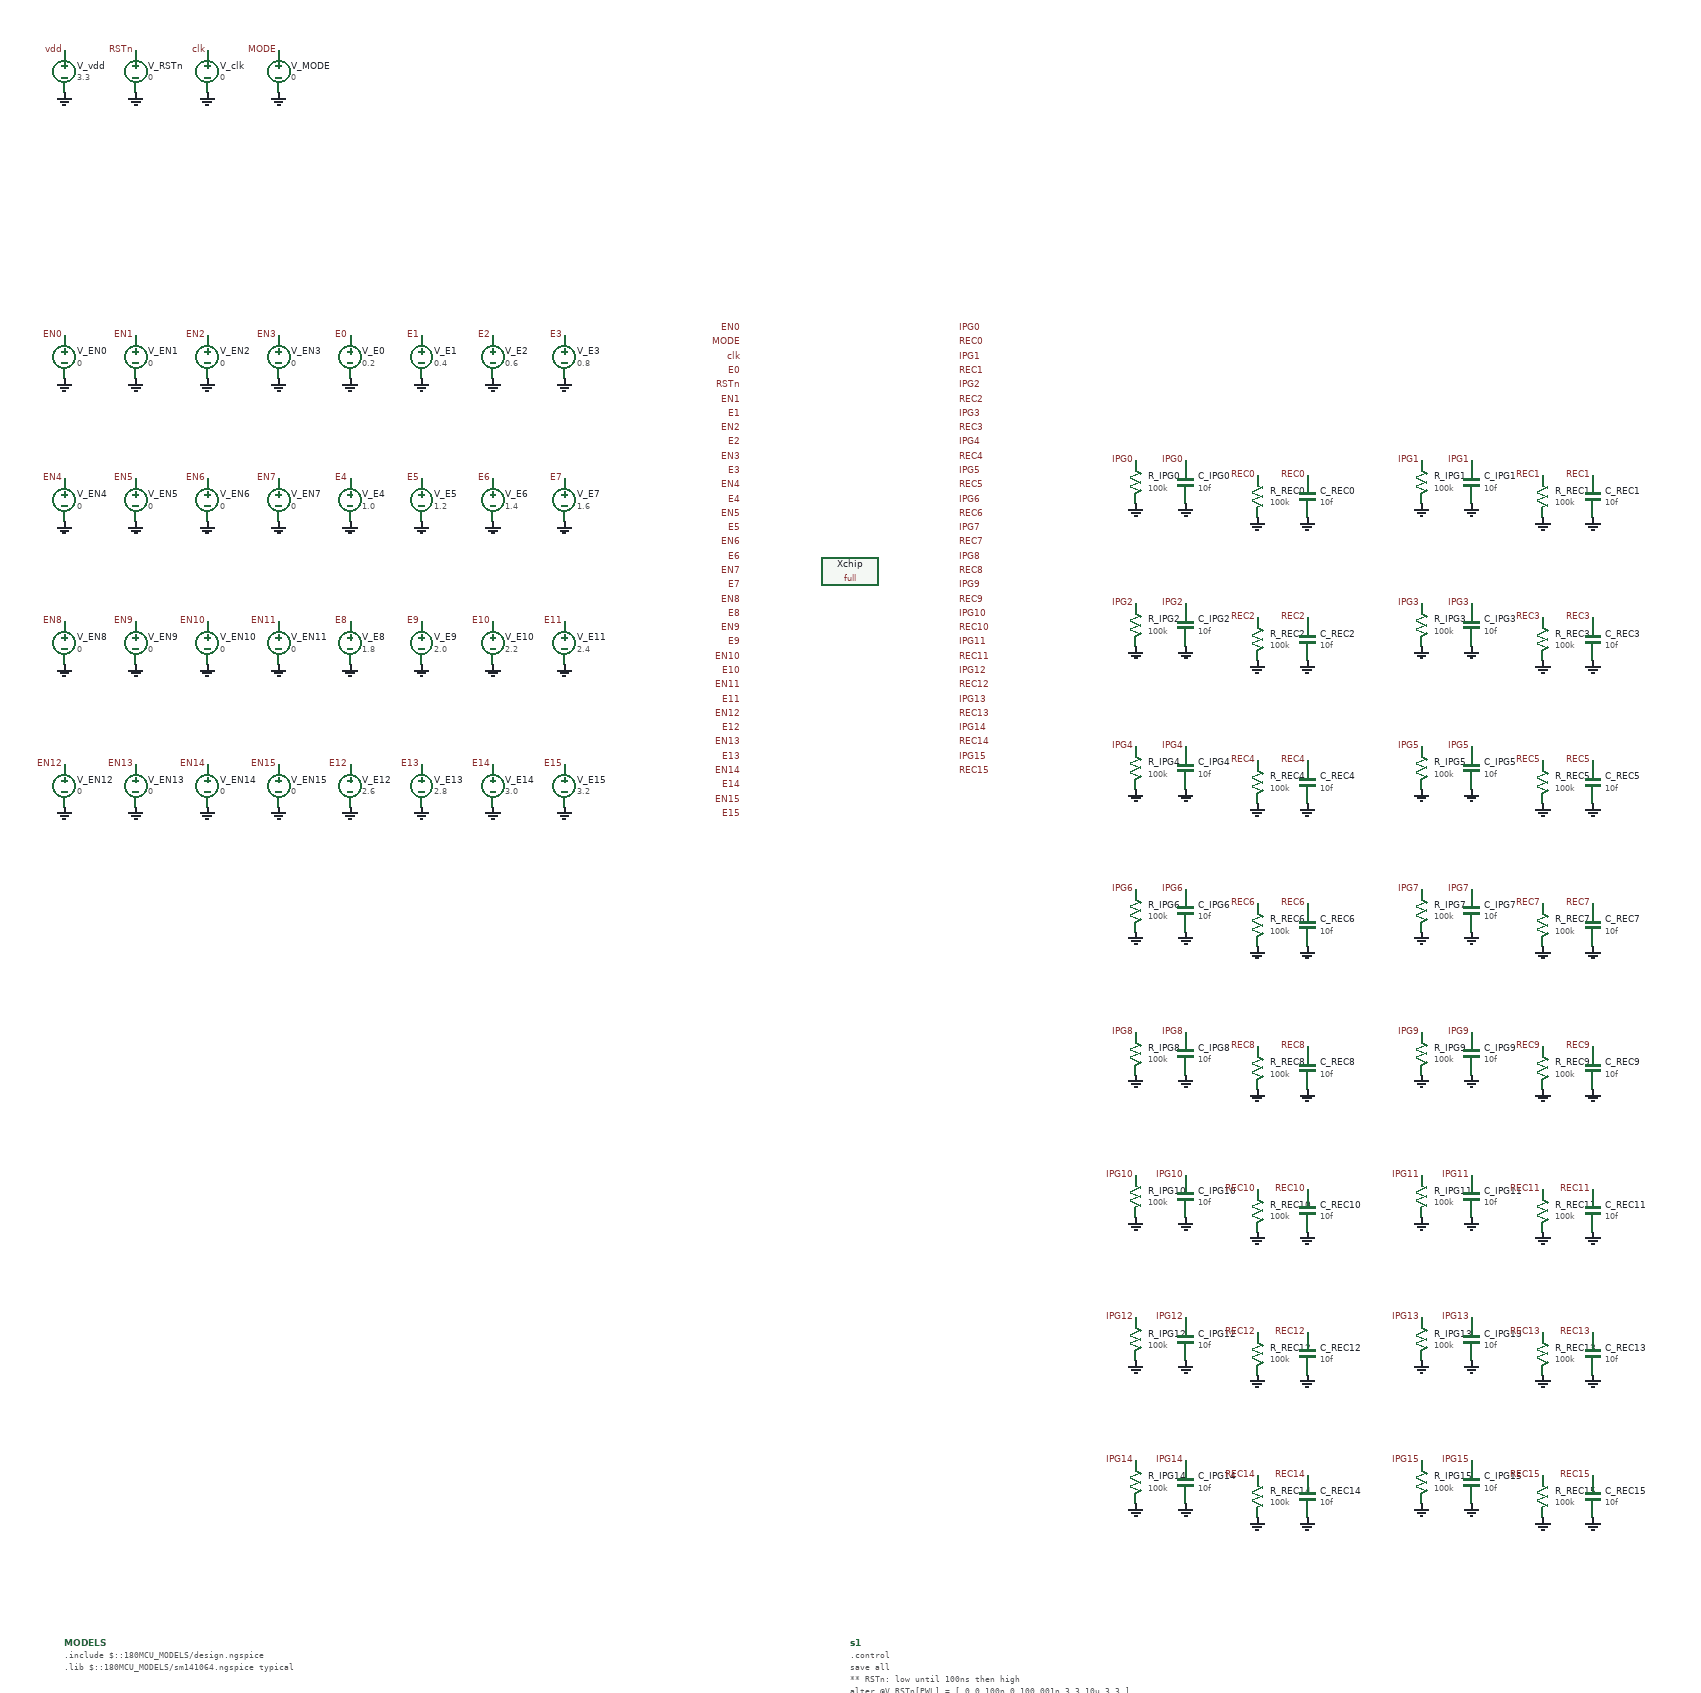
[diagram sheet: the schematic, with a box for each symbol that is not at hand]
v {xschem version=3.4.7 file_version=1.2}
G {}
K {}
V {}
S {}
E {}
C {full.sym} 0 0 0 0 {name=Xchip}
C {lab_wire.sym} -150 -340 0 0 {name=p_EN0_at_chip sig_type=std_logic lab=EN0}
C {lab_wire.sym} -150 -320 0 0 {name=p_MODE_at_chip sig_type=std_logic lab=MODE}
C {lab_wire.sym} -150 -300 0 0 {name=p_clk_at_chip sig_type=std_logic lab=clk}
C {lab_wire.sym} -150 -280 0 0 {name=p_E0_at_chip sig_type=std_logic lab=E0}
C {lab_wire.sym} -150 -260 0 0 {name=p_RSTn_at_chip sig_type=std_logic lab=RSTn}
C {lab_wire.sym} -150 -240 0 0 {name=p_EN1_at_chip sig_type=std_logic lab=EN1}
C {lab_wire.sym} -150 -220 0 0 {name=p_E1_at_chip sig_type=std_logic lab=E1}
C {lab_wire.sym} -150 -200 0 0 {name=p_EN2_at_chip sig_type=std_logic lab=EN2}
C {lab_wire.sym} -150 -180 0 0 {name=p_E2_at_chip sig_type=std_logic lab=E2}
C {lab_wire.sym} -150 -160 0 0 {name=p_EN3_at_chip sig_type=std_logic lab=EN3}
C {lab_wire.sym} -150 -140 0 0 {name=p_E3_at_chip sig_type=std_logic lab=E3}
C {lab_wire.sym} -150 -120 0 0 {name=p_EN4_at_chip sig_type=std_logic lab=EN4}
C {lab_wire.sym} -150 -100 0 0 {name=p_E4_at_chip sig_type=std_logic lab=E4}
C {lab_wire.sym} -150 -80 0 0 {name=p_EN5_at_chip sig_type=std_logic lab=EN5}
C {lab_wire.sym} -150 -60 0 0 {name=p_E5_at_chip sig_type=std_logic lab=E5}
C {lab_wire.sym} -150 -40 0 0 {name=p_EN6_at_chip sig_type=std_logic lab=EN6}
C {lab_wire.sym} -150 -20 0 0 {name=p_E6_at_chip sig_type=std_logic lab=E6}
C {lab_wire.sym} -150 0 0 0 {name=p_EN7_at_chip sig_type=std_logic lab=EN7}
C {lab_wire.sym} -150 20 0 0 {name=p_E7_at_chip sig_type=std_logic lab=E7}
C {lab_wire.sym} -150 40 0 0 {name=p_EN8_at_chip sig_type=std_logic lab=EN8}
C {lab_wire.sym} -150 60 0 0 {name=p_E8_at_chip sig_type=std_logic lab=E8}
C {lab_wire.sym} -150 80 0 0 {name=p_EN9_at_chip sig_type=std_logic lab=EN9}
C {lab_wire.sym} -150 100 0 0 {name=p_E9_at_chip sig_type=std_logic lab=E9}
C {lab_wire.sym} -150 120 0 0 {name=p_EN10_at_chip sig_type=std_logic lab=EN10}
C {lab_wire.sym} -150 140 0 0 {name=p_E10_at_chip sig_type=std_logic lab=E10}
C {lab_wire.sym} -150 160 0 0 {name=p_EN11_at_chip sig_type=std_logic lab=EN11}
C {lab_wire.sym} -150 180 0 0 {name=p_E11_at_chip sig_type=std_logic lab=E11}
C {lab_wire.sym} -150 200 0 0 {name=p_EN12_at_chip sig_type=std_logic lab=EN12}
C {lab_wire.sym} -150 220 0 0 {name=p_E12_at_chip sig_type=std_logic lab=E12}
C {lab_wire.sym} -150 240 0 0 {name=p_EN13_at_chip sig_type=std_logic lab=EN13}
C {lab_wire.sym} -150 260 0 0 {name=p_E13_at_chip sig_type=std_logic lab=E13}
C {lab_wire.sym} -150 280 0 0 {name=p_EN14_at_chip sig_type=std_logic lab=EN14}
C {lab_wire.sym} -150 300 0 0 {name=p_E14_at_chip sig_type=std_logic lab=E14}
C {lab_wire.sym} -150 320 0 0 {name=p_EN15_at_chip sig_type=std_logic lab=EN15}
C {lab_wire.sym} -150 340 0 0 {name=p_E15_at_chip sig_type=std_logic lab=E15}
C {lab_wire.sym} 150 -340 0 1 {name=p_IPG0_at_chip sig_type=std_logic lab=IPG0}
C {lab_wire.sym} 150 -320 0 1 {name=p_REC0_at_chip sig_type=std_logic lab=REC0}
C {lab_wire.sym} 150 -300 0 1 {name=p_IPG1_at_chip sig_type=std_logic lab=IPG1}
C {lab_wire.sym} 150 -280 0 1 {name=p_REC1_at_chip sig_type=std_logic lab=REC1}
C {lab_wire.sym} 150 -260 0 1 {name=p_IPG2_at_chip sig_type=std_logic lab=IPG2}
C {lab_wire.sym} 150 -240 0 1 {name=p_REC2_at_chip sig_type=std_logic lab=REC2}
C {lab_wire.sym} 150 -220 0 1 {name=p_IPG3_at_chip sig_type=std_logic lab=IPG3}
C {lab_wire.sym} 150 -200 0 1 {name=p_REC3_at_chip sig_type=std_logic lab=REC3}
C {lab_wire.sym} 150 -180 0 1 {name=p_IPG4_at_chip sig_type=std_logic lab=IPG4}
C {lab_wire.sym} 150 -160 0 1 {name=p_REC4_at_chip sig_type=std_logic lab=REC4}
C {lab_wire.sym} 150 -140 0 1 {name=p_IPG5_at_chip sig_type=std_logic lab=IPG5}
C {lab_wire.sym} 150 -120 0 1 {name=p_REC5_at_chip sig_type=std_logic lab=REC5}
C {lab_wire.sym} 150 -100 0 1 {name=p_IPG6_at_chip sig_type=std_logic lab=IPG6}
C {lab_wire.sym} 150 -80 0 1 {name=p_REC6_at_chip sig_type=std_logic lab=REC6}
C {lab_wire.sym} 150 -60 0 1 {name=p_IPG7_at_chip sig_type=std_logic lab=IPG7}
C {lab_wire.sym} 150 -40 0 1 {name=p_REC7_at_chip sig_type=std_logic lab=REC7}
C {lab_wire.sym} 150 -20 0 1 {name=p_IPG8_at_chip sig_type=std_logic lab=IPG8}
C {lab_wire.sym} 150 0 0 1 {name=p_REC8_at_chip sig_type=std_logic lab=REC8}
C {lab_wire.sym} 150 20 0 1 {name=p_IPG9_at_chip sig_type=std_logic lab=IPG9}
C {lab_wire.sym} 150 40 0 1 {name=p_REC9_at_chip sig_type=std_logic lab=REC9}
C {lab_wire.sym} 150 60 0 1 {name=p_IPG10_at_chip sig_type=std_logic lab=IPG10}
C {lab_wire.sym} 150 80 0 1 {name=p_REC10_at_chip sig_type=std_logic lab=REC10}
C {lab_wire.sym} 150 100 0 1 {name=p_IPG11_at_chip sig_type=std_logic lab=IPG11}
C {lab_wire.sym} 150 120 0 1 {name=p_REC11_at_chip sig_type=std_logic lab=REC11}
C {lab_wire.sym} 150 140 0 1 {name=p_IPG12_at_chip sig_type=std_logic lab=IPG12}
C {lab_wire.sym} 150 160 0 1 {name=p_REC12_at_chip sig_type=std_logic lab=REC12}
C {lab_wire.sym} 150 180 0 1 {name=p_IPG13_at_chip sig_type=std_logic lab=IPG13}
C {lab_wire.sym} 150 200 0 1 {name=p_REC13_at_chip sig_type=std_logic lab=REC13}
C {lab_wire.sym} 150 220 0 1 {name=p_IPG14_at_chip sig_type=std_logic lab=IPG14}
C {lab_wire.sym} 150 240 0 1 {name=p_REC14_at_chip sig_type=std_logic lab=REC14}
C {lab_wire.sym} 150 260 0 1 {name=p_IPG15_at_chip sig_type=std_logic lab=IPG15}
C {lab_wire.sym} 150 280 0 1 {name=p_REC15_at_chip sig_type=std_logic lab=REC15}
C {vsource.sym} -1100 -700 0 0 {name=V_vdd value=3.3 savecurrent=false}
C {gnd.sym} -1100 -670 0 0 {name=l_vdd lab=GND}
C {lab_wire.sym} -1100 -730 3 0 {name=p_vdd sig_type=std_logic lab=vdd}
C {vsource.sym} -1000 -700 0 0 {name=V_RSTn value=0 savecurrent=false}
C {gnd.sym} -1000 -670 0 0 {name=l_RSTn lab=GND}
C {lab_wire.sym} -1000 -730 3 0 {name=p_RSTn sig_type=std_logic lab=RSTn}
C {vsource.sym} -900 -700 0 0 {name=V_clk value=0 savecurrent=false}
C {gnd.sym} -900 -670 0 0 {name=l_clk lab=GND}
C {lab_wire.sym} -900 -730 3 0 {name=p_clk sig_type=std_logic lab=clk}
C {vsource.sym} -800 -700 0 0 {name=V_MODE value=0 savecurrent=false}
C {gnd.sym} -800 -670 0 0 {name=l_MODE lab=GND}
C {lab_wire.sym} -800 -730 3 0 {name=p_MODE sig_type=std_logic lab=MODE}
C {vsource.sym} -1100 -300 0 0 {name=V_EN0 value=0 savecurrent=false}
C {gnd.sym} -1100 -270 0 0 {name=l_EN0 lab=GND}
C {lab_wire.sym} -1100 -330 3 0 {name=p_VEN0 sig_type=std_logic lab=EN0}
C {vsource.sym} -1000 -300 0 0 {name=V_EN1 value=0 savecurrent=false}
C {gnd.sym} -1000 -270 0 0 {name=l_EN1 lab=GND}
C {lab_wire.sym} -1000 -330 3 0 {name=p_VEN1 sig_type=std_logic lab=EN1}
C {vsource.sym} -900 -300 0 0 {name=V_EN2 value=0 savecurrent=false}
C {gnd.sym} -900 -270 0 0 {name=l_EN2 lab=GND}
C {lab_wire.sym} -900 -330 3 0 {name=p_VEN2 sig_type=std_logic lab=EN2}
C {vsource.sym} -800 -300 0 0 {name=V_EN3 value=0 savecurrent=false}
C {gnd.sym} -800 -270 0 0 {name=l_EN3 lab=GND}
C {lab_wire.sym} -800 -330 3 0 {name=p_VEN3 sig_type=std_logic lab=EN3}
C {vsource.sym} -1100 -100 0 0 {name=V_EN4 value=0 savecurrent=false}
C {gnd.sym} -1100 -70 0 0 {name=l_EN4 lab=GND}
C {lab_wire.sym} -1100 -130 3 0 {name=p_VEN4 sig_type=std_logic lab=EN4}
C {vsource.sym} -1000 -100 0 0 {name=V_EN5 value=0 savecurrent=false}
C {gnd.sym} -1000 -70 0 0 {name=l_EN5 lab=GND}
C {lab_wire.sym} -1000 -130 3 0 {name=p_VEN5 sig_type=std_logic lab=EN5}
C {vsource.sym} -900 -100 0 0 {name=V_EN6 value=0 savecurrent=false}
C {gnd.sym} -900 -70 0 0 {name=l_EN6 lab=GND}
C {lab_wire.sym} -900 -130 3 0 {name=p_VEN6 sig_type=std_logic lab=EN6}
C {vsource.sym} -800 -100 0 0 {name=V_EN7 value=0 savecurrent=false}
C {gnd.sym} -800 -70 0 0 {name=l_EN7 lab=GND}
C {lab_wire.sym} -800 -130 3 0 {name=p_VEN7 sig_type=std_logic lab=EN7}
C {vsource.sym} -1100 100 0 0 {name=V_EN8 value=0 savecurrent=false}
C {gnd.sym} -1100 130 0 0 {name=l_EN8 lab=GND}
C {lab_wire.sym} -1100 70 3 0 {name=p_VEN8 sig_type=std_logic lab=EN8}
C {vsource.sym} -1000 100 0 0 {name=V_EN9 value=0 savecurrent=false}
C {gnd.sym} -1000 130 0 0 {name=l_EN9 lab=GND}
C {lab_wire.sym} -1000 70 3 0 {name=p_VEN9 sig_type=std_logic lab=EN9}
C {vsource.sym} -900 100 0 0 {name=V_EN10 value=0 savecurrent=false}
C {gnd.sym} -900 130 0 0 {name=l_EN10 lab=GND}
C {lab_wire.sym} -900 70 3 0 {name=p_VEN10 sig_type=std_logic lab=EN10}
C {vsource.sym} -800 100 0 0 {name=V_EN11 value=0 savecurrent=false}
C {gnd.sym} -800 130 0 0 {name=l_EN11 lab=GND}
C {lab_wire.sym} -800 70 3 0 {name=p_VEN11 sig_type=std_logic lab=EN11}
C {vsource.sym} -1100 300 0 0 {name=V_EN12 value=0 savecurrent=false}
C {gnd.sym} -1100 330 0 0 {name=l_EN12 lab=GND}
C {lab_wire.sym} -1100 270 3 0 {name=p_VEN12 sig_type=std_logic lab=EN12}
C {vsource.sym} -1000 300 0 0 {name=V_EN13 value=0 savecurrent=false}
C {gnd.sym} -1000 330 0 0 {name=l_EN13 lab=GND}
C {lab_wire.sym} -1000 270 3 0 {name=p_VEN13 sig_type=std_logic lab=EN13}
C {vsource.sym} -900 300 0 0 {name=V_EN14 value=0 savecurrent=false}
C {gnd.sym} -900 330 0 0 {name=l_EN14 lab=GND}
C {lab_wire.sym} -900 270 3 0 {name=p_VEN14 sig_type=std_logic lab=EN14}
C {vsource.sym} -800 300 0 0 {name=V_EN15 value=0 savecurrent=false}
C {gnd.sym} -800 330 0 0 {name=l_EN15 lab=GND}
C {lab_wire.sym} -800 270 3 0 {name=p_VEN15 sig_type=std_logic lab=EN15}
C {vsource.sym} -700 -300 0 0 {name=V_E0 value=0.2 savecurrent=false}
C {gnd.sym} -700 -270 0 0 {name=l_E0 lab=GND}
C {lab_wire.sym} -700 -330 3 0 {name=p_VE0 sig_type=std_logic lab=E0}
C {vsource.sym} -600 -300 0 0 {name=V_E1 value=0.4 savecurrent=false}
C {gnd.sym} -600 -270 0 0 {name=l_E1 lab=GND}
C {lab_wire.sym} -600 -330 3 0 {name=p_VE1 sig_type=std_logic lab=E1}
C {vsource.sym} -500 -300 0 0 {name=V_E2 value=0.6 savecurrent=false}
C {gnd.sym} -500 -270 0 0 {name=l_E2 lab=GND}
C {lab_wire.sym} -500 -330 3 0 {name=p_VE2 sig_type=std_logic lab=E2}
C {vsource.sym} -400 -300 0 0 {name=V_E3 value=0.8 savecurrent=false}
C {gnd.sym} -400 -270 0 0 {name=l_E3 lab=GND}
C {lab_wire.sym} -400 -330 3 0 {name=p_VE3 sig_type=std_logic lab=E3}
C {vsource.sym} -700 -100 0 0 {name=V_E4 value=1.0 savecurrent=false}
C {gnd.sym} -700 -70 0 0 {name=l_E4 lab=GND}
C {lab_wire.sym} -700 -130 3 0 {name=p_VE4 sig_type=std_logic lab=E4}
C {vsource.sym} -600 -100 0 0 {name=V_E5 value=1.2 savecurrent=false}
C {gnd.sym} -600 -70 0 0 {name=l_E5 lab=GND}
C {lab_wire.sym} -600 -130 3 0 {name=p_VE5 sig_type=std_logic lab=E5}
C {vsource.sym} -500 -100 0 0 {name=V_E6 value=1.4 savecurrent=false}
C {gnd.sym} -500 -70 0 0 {name=l_E6 lab=GND}
C {lab_wire.sym} -500 -130 3 0 {name=p_VE6 sig_type=std_logic lab=E6}
C {vsource.sym} -400 -100 0 0 {name=V_E7 value=1.6 savecurrent=false}
C {gnd.sym} -400 -70 0 0 {name=l_E7 lab=GND}
C {lab_wire.sym} -400 -130 3 0 {name=p_VE7 sig_type=std_logic lab=E7}
C {vsource.sym} -700 100 0 0 {name=V_E8 value=1.8 savecurrent=false}
C {gnd.sym} -700 130 0 0 {name=l_E8 lab=GND}
C {lab_wire.sym} -700 70 3 0 {name=p_VE8 sig_type=std_logic lab=E8}
C {vsource.sym} -600 100 0 0 {name=V_E9 value=2.0 savecurrent=false}
C {gnd.sym} -600 130 0 0 {name=l_E9 lab=GND}
C {lab_wire.sym} -600 70 3 0 {name=p_VE9 sig_type=std_logic lab=E9}
C {vsource.sym} -500 100 0 0 {name=V_E10 value=2.2 savecurrent=false}
C {gnd.sym} -500 130 0 0 {name=l_E10 lab=GND}
C {lab_wire.sym} -500 70 3 0 {name=p_VE10 sig_type=std_logic lab=E10}
C {vsource.sym} -400 100 0 0 {name=V_E11 value=2.4 savecurrent=false}
C {gnd.sym} -400 130 0 0 {name=l_E11 lab=GND}
C {lab_wire.sym} -400 70 3 0 {name=p_VE11 sig_type=std_logic lab=E11}
C {vsource.sym} -700 300 0 0 {name=V_E12 value=2.6 savecurrent=false}
C {gnd.sym} -700 330 0 0 {name=l_E12 lab=GND}
C {lab_wire.sym} -700 270 3 0 {name=p_VE12 sig_type=std_logic lab=E12}
C {vsource.sym} -600 300 0 0 {name=V_E13 value=2.8 savecurrent=false}
C {gnd.sym} -600 330 0 0 {name=l_E13 lab=GND}
C {lab_wire.sym} -600 270 3 0 {name=p_VE13 sig_type=std_logic lab=E13}
C {vsource.sym} -500 300 0 0 {name=V_E14 value=3.0 savecurrent=false}
C {gnd.sym} -500 330 0 0 {name=l_E14 lab=GND}
C {lab_wire.sym} -500 270 3 0 {name=p_VE14 sig_type=std_logic lab=E14}
C {vsource.sym} -400 300 0 0 {name=V_E15 value=3.2 savecurrent=false}
C {gnd.sym} -400 330 0 0 {name=l_E15 lab=GND}
C {lab_wire.sym} -400 270 3 0 {name=p_VE15 sig_type=std_logic lab=E15}
C {res.sym} 400 -125 0 0 {name=R_IPG0 value=100k device=resistor m=1}
C {gnd.sym} 400 -95 0 0 {name=lR_IPG0 lab=GND}
C {lab_wire.sym} 400 -155 3 0 {name=pR_IPG0 sig_type=std_logic lab=IPG0}
C {capa.sym} 470 -125 0 0 {name=C_IPG0 value=10f m=1 device="ceramic capacitor"}
C {gnd.sym} 470 -95 0 0 {name=lC_IPG0 lab=GND}
C {lab_wire.sym} 470 -155 3 0 {name=pC_IPG0 sig_type=std_logic lab=IPG0}
C {res.sym} 570 -105 0 0 {name=R_REC0 value=100k device=resistor m=1}
C {gnd.sym} 570 -75 0 0 {name=lR_REC0 lab=GND}
C {lab_wire.sym} 570 -135 3 0 {name=pR_REC0 sig_type=std_logic lab=REC0}
C {capa.sym} 640 -105 0 0 {name=C_REC0 value=10f m=1 device="ceramic capacitor"}
C {gnd.sym} 640 -75 0 0 {name=lC_REC0 lab=GND}
C {lab_wire.sym} 640 -135 3 0 {name=pC_REC0 sig_type=std_logic lab=REC0}
C {res.sym} 800 -125 0 0 {name=R_IPG1 value=100k device=resistor m=1}
C {gnd.sym} 800 -95 0 0 {name=lR_IPG1 lab=GND}
C {lab_wire.sym} 800 -155 3 0 {name=pR_IPG1 sig_type=std_logic lab=IPG1}
C {capa.sym} 870 -125 0 0 {name=C_IPG1 value=10f m=1 device="ceramic capacitor"}
C {gnd.sym} 870 -95 0 0 {name=lC_IPG1 lab=GND}
C {lab_wire.sym} 870 -155 3 0 {name=pC_IPG1 sig_type=std_logic lab=IPG1}
C {res.sym} 970 -105 0 0 {name=R_REC1 value=100k device=resistor m=1}
C {gnd.sym} 970 -75 0 0 {name=lR_REC1 lab=GND}
C {lab_wire.sym} 970 -135 3 0 {name=pR_REC1 sig_type=std_logic lab=REC1}
C {capa.sym} 1040 -105 0 0 {name=C_REC1 value=10f m=1 device="ceramic capacitor"}
C {gnd.sym} 1040 -75 0 0 {name=lC_REC1 lab=GND}
C {lab_wire.sym} 1040 -135 3 0 {name=pC_REC1 sig_type=std_logic lab=REC1}
C {res.sym} 400 75 0 0 {name=R_IPG2 value=100k device=resistor m=1}
C {gnd.sym} 400 105 0 0 {name=lR_IPG2 lab=GND}
C {lab_wire.sym} 400 45 3 0 {name=pR_IPG2 sig_type=std_logic lab=IPG2}
C {capa.sym} 470 75 0 0 {name=C_IPG2 value=10f m=1 device="ceramic capacitor"}
C {gnd.sym} 470 105 0 0 {name=lC_IPG2 lab=GND}
C {lab_wire.sym} 470 45 3 0 {name=pC_IPG2 sig_type=std_logic lab=IPG2}
C {res.sym} 570 95 0 0 {name=R_REC2 value=100k device=resistor m=1}
C {gnd.sym} 570 125 0 0 {name=lR_REC2 lab=GND}
C {lab_wire.sym} 570 65 3 0 {name=pR_REC2 sig_type=std_logic lab=REC2}
C {capa.sym} 640 95 0 0 {name=C_REC2 value=10f m=1 device="ceramic capacitor"}
C {gnd.sym} 640 125 0 0 {name=lC_REC2 lab=GND}
C {lab_wire.sym} 640 65 3 0 {name=pC_REC2 sig_type=std_logic lab=REC2}
C {res.sym} 800 75 0 0 {name=R_IPG3 value=100k device=resistor m=1}
C {gnd.sym} 800 105 0 0 {name=lR_IPG3 lab=GND}
C {lab_wire.sym} 800 45 3 0 {name=pR_IPG3 sig_type=std_logic lab=IPG3}
C {capa.sym} 870 75 0 0 {name=C_IPG3 value=10f m=1 device="ceramic capacitor"}
C {gnd.sym} 870 105 0 0 {name=lC_IPG3 lab=GND}
C {lab_wire.sym} 870 45 3 0 {name=pC_IPG3 sig_type=std_logic lab=IPG3}
C {res.sym} 970 95 0 0 {name=R_REC3 value=100k device=resistor m=1}
C {gnd.sym} 970 125 0 0 {name=lR_REC3 lab=GND}
C {lab_wire.sym} 970 65 3 0 {name=pR_REC3 sig_type=std_logic lab=REC3}
C {capa.sym} 1040 95 0 0 {name=C_REC3 value=10f m=1 device="ceramic capacitor"}
C {gnd.sym} 1040 125 0 0 {name=lC_REC3 lab=GND}
C {lab_wire.sym} 1040 65 3 0 {name=pC_REC3 sig_type=std_logic lab=REC3}
C {res.sym} 400 275 0 0 {name=R_IPG4 value=100k device=resistor m=1}
C {gnd.sym} 400 305 0 0 {name=lR_IPG4 lab=GND}
C {lab_wire.sym} 400 245 3 0 {name=pR_IPG4 sig_type=std_logic lab=IPG4}
C {capa.sym} 470 275 0 0 {name=C_IPG4 value=10f m=1 device="ceramic capacitor"}
C {gnd.sym} 470 305 0 0 {name=lC_IPG4 lab=GND}
C {lab_wire.sym} 470 245 3 0 {name=pC_IPG4 sig_type=std_logic lab=IPG4}
C {res.sym} 570 295 0 0 {name=R_REC4 value=100k device=resistor m=1}
C {gnd.sym} 570 325 0 0 {name=lR_REC4 lab=GND}
C {lab_wire.sym} 570 265 3 0 {name=pR_REC4 sig_type=std_logic lab=REC4}
C {capa.sym} 640 295 0 0 {name=C_REC4 value=10f m=1 device="ceramic capacitor"}
C {gnd.sym} 640 325 0 0 {name=lC_REC4 lab=GND}
C {lab_wire.sym} 640 265 3 0 {name=pC_REC4 sig_type=std_logic lab=REC4}
C {res.sym} 800 275 0 0 {name=R_IPG5 value=100k device=resistor m=1}
C {gnd.sym} 800 305 0 0 {name=lR_IPG5 lab=GND}
C {lab_wire.sym} 800 245 3 0 {name=pR_IPG5 sig_type=std_logic lab=IPG5}
C {capa.sym} 870 275 0 0 {name=C_IPG5 value=10f m=1 device="ceramic capacitor"}
C {gnd.sym} 870 305 0 0 {name=lC_IPG5 lab=GND}
C {lab_wire.sym} 870 245 3 0 {name=pC_IPG5 sig_type=std_logic lab=IPG5}
C {res.sym} 970 295 0 0 {name=R_REC5 value=100k device=resistor m=1}
C {gnd.sym} 970 325 0 0 {name=lR_REC5 lab=GND}
C {lab_wire.sym} 970 265 3 0 {name=pR_REC5 sig_type=std_logic lab=REC5}
C {capa.sym} 1040 295 0 0 {name=C_REC5 value=10f m=1 device="ceramic capacitor"}
C {gnd.sym} 1040 325 0 0 {name=lC_REC5 lab=GND}
C {lab_wire.sym} 1040 265 3 0 {name=pC_REC5 sig_type=std_logic lab=REC5}
C {res.sym} 400 475 0 0 {name=R_IPG6 value=100k device=resistor m=1}
C {gnd.sym} 400 505 0 0 {name=lR_IPG6 lab=GND}
C {lab_wire.sym} 400 445 3 0 {name=pR_IPG6 sig_type=std_logic lab=IPG6}
C {capa.sym} 470 475 0 0 {name=C_IPG6 value=10f m=1 device="ceramic capacitor"}
C {gnd.sym} 470 505 0 0 {name=lC_IPG6 lab=GND}
C {lab_wire.sym} 470 445 3 0 {name=pC_IPG6 sig_type=std_logic lab=IPG6}
C {res.sym} 570 495 0 0 {name=R_REC6 value=100k device=resistor m=1}
C {gnd.sym} 570 525 0 0 {name=lR_REC6 lab=GND}
C {lab_wire.sym} 570 465 3 0 {name=pR_REC6 sig_type=std_logic lab=REC6}
C {capa.sym} 640 495 0 0 {name=C_REC6 value=10f m=1 device="ceramic capacitor"}
C {gnd.sym} 640 525 0 0 {name=lC_REC6 lab=GND}
C {lab_wire.sym} 640 465 3 0 {name=pC_REC6 sig_type=std_logic lab=REC6}
C {res.sym} 800 475 0 0 {name=R_IPG7 value=100k device=resistor m=1}
C {gnd.sym} 800 505 0 0 {name=lR_IPG7 lab=GND}
C {lab_wire.sym} 800 445 3 0 {name=pR_IPG7 sig_type=std_logic lab=IPG7}
C {capa.sym} 870 475 0 0 {name=C_IPG7 value=10f m=1 device="ceramic capacitor"}
C {gnd.sym} 870 505 0 0 {name=lC_IPG7 lab=GND}
C {lab_wire.sym} 870 445 3 0 {name=pC_IPG7 sig_type=std_logic lab=IPG7}
C {res.sym} 970 495 0 0 {name=R_REC7 value=100k device=resistor m=1}
C {gnd.sym} 970 525 0 0 {name=lR_REC7 lab=GND}
C {lab_wire.sym} 970 465 3 0 {name=pR_REC7 sig_type=std_logic lab=REC7}
C {capa.sym} 1040 495 0 0 {name=C_REC7 value=10f m=1 device="ceramic capacitor"}
C {gnd.sym} 1040 525 0 0 {name=lC_REC7 lab=GND}
C {lab_wire.sym} 1040 465 3 0 {name=pC_REC7 sig_type=std_logic lab=REC7}
C {res.sym} 400 675 0 0 {name=R_IPG8 value=100k device=resistor m=1}
C {gnd.sym} 400 705 0 0 {name=lR_IPG8 lab=GND}
C {lab_wire.sym} 400 645 3 0 {name=pR_IPG8 sig_type=std_logic lab=IPG8}
C {capa.sym} 470 675 0 0 {name=C_IPG8 value=10f m=1 device="ceramic capacitor"}
C {gnd.sym} 470 705 0 0 {name=lC_IPG8 lab=GND}
C {lab_wire.sym} 470 645 3 0 {name=pC_IPG8 sig_type=std_logic lab=IPG8}
C {res.sym} 570 695 0 0 {name=R_REC8 value=100k device=resistor m=1}
C {gnd.sym} 570 725 0 0 {name=lR_REC8 lab=GND}
C {lab_wire.sym} 570 665 3 0 {name=pR_REC8 sig_type=std_logic lab=REC8}
C {capa.sym} 640 695 0 0 {name=C_REC8 value=10f m=1 device="ceramic capacitor"}
C {gnd.sym} 640 725 0 0 {name=lC_REC8 lab=GND}
C {lab_wire.sym} 640 665 3 0 {name=pC_REC8 sig_type=std_logic lab=REC8}
C {res.sym} 800 675 0 0 {name=R_IPG9 value=100k device=resistor m=1}
C {gnd.sym} 800 705 0 0 {name=lR_IPG9 lab=GND}
C {lab_wire.sym} 800 645 3 0 {name=pR_IPG9 sig_type=std_logic lab=IPG9}
C {capa.sym} 870 675 0 0 {name=C_IPG9 value=10f m=1 device="ceramic capacitor"}
C {gnd.sym} 870 705 0 0 {name=lC_IPG9 lab=GND}
C {lab_wire.sym} 870 645 3 0 {name=pC_IPG9 sig_type=std_logic lab=IPG9}
C {res.sym} 970 695 0 0 {name=R_REC9 value=100k device=resistor m=1}
C {gnd.sym} 970 725 0 0 {name=lR_REC9 lab=GND}
C {lab_wire.sym} 970 665 3 0 {name=pR_REC9 sig_type=std_logic lab=REC9}
C {capa.sym} 1040 695 0 0 {name=C_REC9 value=10f m=1 device="ceramic capacitor"}
C {gnd.sym} 1040 725 0 0 {name=lC_REC9 lab=GND}
C {lab_wire.sym} 1040 665 3 0 {name=pC_REC9 sig_type=std_logic lab=REC9}
C {res.sym} 400 875 0 0 {name=R_IPG10 value=100k device=resistor m=1}
C {gnd.sym} 400 905 0 0 {name=lR_IPG10 lab=GND}
C {lab_wire.sym} 400 845 3 0 {name=pR_IPG10 sig_type=std_logic lab=IPG10}
C {capa.sym} 470 875 0 0 {name=C_IPG10 value=10f m=1 device="ceramic capacitor"}
C {gnd.sym} 470 905 0 0 {name=lC_IPG10 lab=GND}
C {lab_wire.sym} 470 845 3 0 {name=pC_IPG10 sig_type=std_logic lab=IPG10}
C {res.sym} 570 895 0 0 {name=R_REC10 value=100k device=resistor m=1}
C {gnd.sym} 570 925 0 0 {name=lR_REC10 lab=GND}
C {lab_wire.sym} 570 865 3 0 {name=pR_REC10 sig_type=std_logic lab=REC10}
C {capa.sym} 640 895 0 0 {name=C_REC10 value=10f m=1 device="ceramic capacitor"}
C {gnd.sym} 640 925 0 0 {name=lC_REC10 lab=GND}
C {lab_wire.sym} 640 865 3 0 {name=pC_REC10 sig_type=std_logic lab=REC10}
C {res.sym} 800 875 0 0 {name=R_IPG11 value=100k device=resistor m=1}
C {gnd.sym} 800 905 0 0 {name=lR_IPG11 lab=GND}
C {lab_wire.sym} 800 845 3 0 {name=pR_IPG11 sig_type=std_logic lab=IPG11}
C {capa.sym} 870 875 0 0 {name=C_IPG11 value=10f m=1 device="ceramic capacitor"}
C {gnd.sym} 870 905 0 0 {name=lC_IPG11 lab=GND}
C {lab_wire.sym} 870 845 3 0 {name=pC_IPG11 sig_type=std_logic lab=IPG11}
C {res.sym} 970 895 0 0 {name=R_REC11 value=100k device=resistor m=1}
C {gnd.sym} 970 925 0 0 {name=lR_REC11 lab=GND}
C {lab_wire.sym} 970 865 3 0 {name=pR_REC11 sig_type=std_logic lab=REC11}
C {capa.sym} 1040 895 0 0 {name=C_REC11 value=10f m=1 device="ceramic capacitor"}
C {gnd.sym} 1040 925 0 0 {name=lC_REC11 lab=GND}
C {lab_wire.sym} 1040 865 3 0 {name=pC_REC11 sig_type=std_logic lab=REC11}
C {res.sym} 400 1075 0 0 {name=R_IPG12 value=100k device=resistor m=1}
C {gnd.sym} 400 1105 0 0 {name=lR_IPG12 lab=GND}
C {lab_wire.sym} 400 1045 3 0 {name=pR_IPG12 sig_type=std_logic lab=IPG12}
C {capa.sym} 470 1075 0 0 {name=C_IPG12 value=10f m=1 device="ceramic capacitor"}
C {gnd.sym} 470 1105 0 0 {name=lC_IPG12 lab=GND}
C {lab_wire.sym} 470 1045 3 0 {name=pC_IPG12 sig_type=std_logic lab=IPG12}
C {res.sym} 570 1095 0 0 {name=R_REC12 value=100k device=resistor m=1}
C {gnd.sym} 570 1125 0 0 {name=lR_REC12 lab=GND}
C {lab_wire.sym} 570 1065 3 0 {name=pR_REC12 sig_type=std_logic lab=REC12}
C {capa.sym} 640 1095 0 0 {name=C_REC12 value=10f m=1 device="ceramic capacitor"}
C {gnd.sym} 640 1125 0 0 {name=lC_REC12 lab=GND}
C {lab_wire.sym} 640 1065 3 0 {name=pC_REC12 sig_type=std_logic lab=REC12}
C {res.sym} 800 1075 0 0 {name=R_IPG13 value=100k device=resistor m=1}
C {gnd.sym} 800 1105 0 0 {name=lR_IPG13 lab=GND}
C {lab_wire.sym} 800 1045 3 0 {name=pR_IPG13 sig_type=std_logic lab=IPG13}
C {capa.sym} 870 1075 0 0 {name=C_IPG13 value=10f m=1 device="ceramic capacitor"}
C {gnd.sym} 870 1105 0 0 {name=lC_IPG13 lab=GND}
C {lab_wire.sym} 870 1045 3 0 {name=pC_IPG13 sig_type=std_logic lab=IPG13}
C {res.sym} 970 1095 0 0 {name=R_REC13 value=100k device=resistor m=1}
C {gnd.sym} 970 1125 0 0 {name=lR_REC13 lab=GND}
C {lab_wire.sym} 970 1065 3 0 {name=pR_REC13 sig_type=std_logic lab=REC13}
C {capa.sym} 1040 1095 0 0 {name=C_REC13 value=10f m=1 device="ceramic capacitor"}
C {gnd.sym} 1040 1125 0 0 {name=lC_REC13 lab=GND}
C {lab_wire.sym} 1040 1065 3 0 {name=pC_REC13 sig_type=std_logic lab=REC13}
C {res.sym} 400 1275 0 0 {name=R_IPG14 value=100k device=resistor m=1}
C {gnd.sym} 400 1305 0 0 {name=lR_IPG14 lab=GND}
C {lab_wire.sym} 400 1245 3 0 {name=pR_IPG14 sig_type=std_logic lab=IPG14}
C {capa.sym} 470 1275 0 0 {name=C_IPG14 value=10f m=1 device="ceramic capacitor"}
C {gnd.sym} 470 1305 0 0 {name=lC_IPG14 lab=GND}
C {lab_wire.sym} 470 1245 3 0 {name=pC_IPG14 sig_type=std_logic lab=IPG14}
C {res.sym} 570 1295 0 0 {name=R_REC14 value=100k device=resistor m=1}
C {gnd.sym} 570 1325 0 0 {name=lR_REC14 lab=GND}
C {lab_wire.sym} 570 1265 3 0 {name=pR_REC14 sig_type=std_logic lab=REC14}
C {capa.sym} 640 1295 0 0 {name=C_REC14 value=10f m=1 device="ceramic capacitor"}
C {gnd.sym} 640 1325 0 0 {name=lC_REC14 lab=GND}
C {lab_wire.sym} 640 1265 3 0 {name=pC_REC14 sig_type=std_logic lab=REC14}
C {res.sym} 800 1275 0 0 {name=R_IPG15 value=100k device=resistor m=1}
C {gnd.sym} 800 1305 0 0 {name=lR_IPG15 lab=GND}
C {lab_wire.sym} 800 1245 3 0 {name=pR_IPG15 sig_type=std_logic lab=IPG15}
C {capa.sym} 870 1275 0 0 {name=C_IPG15 value=10f m=1 device="ceramic capacitor"}
C {gnd.sym} 870 1305 0 0 {name=lC_IPG15 lab=GND}
C {lab_wire.sym} 870 1245 3 0 {name=pC_IPG15 sig_type=std_logic lab=IPG15}
C {res.sym} 970 1295 0 0 {name=R_REC15 value=100k device=resistor m=1}
C {gnd.sym} 970 1325 0 0 {name=lR_REC15 lab=GND}
C {lab_wire.sym} 970 1265 3 0 {name=pR_REC15 sig_type=std_logic lab=REC15}
C {capa.sym} 1040 1295 0 0 {name=C_REC15 value=10f m=1 device="ceramic capacitor"}
C {gnd.sym} 1040 1325 0 0 {name=lC_REC15 lab=GND}
C {lab_wire.sym} 1040 1265 3 0 {name=pC_REC15 sig_type=std_logic lab=REC15}
C {devices/code_shown.sym} -1100 1500 0 0 {name=MODELS only_toplevel=true
format="tcleval( @value )"
value="
.include $::180MCU_MODELS/design.ngspice
.lib $::180MCU_MODELS/sm141064.ngspice typical
"}
C {code_shown.sym} 0 1500 0 0 {name=s1 only_toplevel=false value="
.control
save all

** RSTn: low until 100ns then high
alter @V_RSTn[PWL] = [ 0 0  100n 0  100.001n 3.3  10u 3.3 ]

** Single latching clock pulse around 200ns
alter @V_clk[PWL] = [ 0 0  200n 0  200.001n 3.3  300n 3.3  300.001n 0  10u 0 ]

** MODE: 0 (stim) for 0..500ns, 1 (record) thereafter
alter @V_MODE[PWL] = [ 0 0  500n 0  500.001n 3.3  10u 3.3 ]

** All 16 EN bits asserted at 150 ns
alter @V_EN0[PWL]  = [ 0 0  150n 0  150.001n 3.3  10u 3.3 ]
alter @V_EN1[PWL]  = [ 0 0  150n 0  150.001n 3.3  10u 3.3 ]
alter @V_EN2[PWL]  = [ 0 0  150n 0  150.001n 3.3  10u 3.3 ]
alter @V_EN3[PWL]  = [ 0 0  150n 0  150.001n 3.3  10u 3.3 ]
alter @V_EN4[PWL]  = [ 0 0  150n 0  150.001n 3.3  10u 3.3 ]
alter @V_EN5[PWL]  = [ 0 0  150n 0  150.001n 3.3  10u 3.3 ]
alter @V_EN6[PWL]  = [ 0 0  150n 0  150.001n 3.3  10u 3.3 ]
alter @V_EN7[PWL]  = [ 0 0  150n 0  150.001n 3.3  10u 3.3 ]
alter @V_EN8[PWL]  = [ 0 0  150n 0  150.001n 3.3  10u 3.3 ]
alter @V_EN9[PWL]  = [ 0 0  150n 0  150.001n 3.3  10u 3.3 ]
alter @V_EN10[PWL] = [ 0 0  150n 0  150.001n 3.3  10u 3.3 ]
alter @V_EN11[PWL] = [ 0 0  150n 0  150.001n 3.3  10u 3.3 ]
alter @V_EN12[PWL] = [ 0 0  150n 0  150.001n 3.3  10u 3.3 ]
alter @V_EN13[PWL] = [ 0 0  150n 0  150.001n 3.3  10u 3.3 ]
alter @V_EN14[PWL] = [ 0 0  150n 0  150.001n 3.3  10u 3.3 ]
alter @V_EN15[PWL] = [ 0 0  150n 0  150.001n 3.3  10u 3.3 ]

tran 1n 800n
write tb_full_chip.raw
.endc
"}
